VERSION 5.7 ;
  NOWIREEXTENSIONATPIN ON ;
  DIVIDERCHAR "/" ;
  BUSBITCHARS "[]" ;
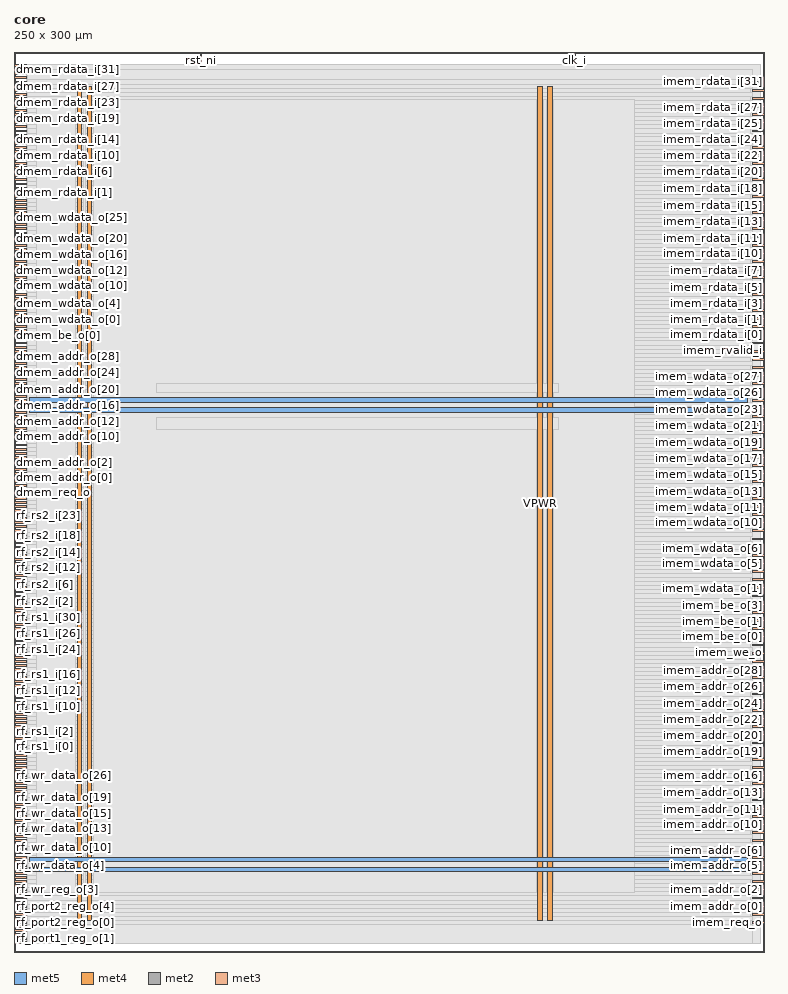
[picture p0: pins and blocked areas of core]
MACRO core
  CLASS BLOCK ;
  FOREIGN core ;
  ORIGIN 0.000 0.000 ;
  SIZE 250.000 BY 300.000 ;
  PIN VGND
    USE GROUND ;
    PORT
      LAYER met5 ;
        RECT 5.280 183.210 244.500 184.810 ;
    END
    PORT
      LAYER met5 ;
        RECT 5.280 30.030 244.500 31.630 ;
    END
    PORT
      LAYER met4 ;
        RECT 177.940 10.640 179.540 288.560 ;
    END
    PORT
      LAYER met4 ;
        RECT 24.340 10.640 25.940 288.560 ;
    END
  END VGND
  PIN VPWR
    USE POWER ;
    PORT
      LAYER met5 ;
        RECT 5.280 179.910 244.500 181.510 ;
    END
    PORT
      LAYER met5 ;
        RECT 5.280 26.730 244.500 28.330 ;
    END
    PORT
      LAYER met4 ;
        RECT 174.640 10.640 176.240 288.560 ;
    END
    PORT
      LAYER met4 ;
        RECT 21.040 10.640 22.640 288.560 ;
    END
  END VPWR
  PIN clk_i
    PORT
      LAYER met2 ;
        RECT 186.850 296.000 187.130 300.000 ;
    END
  END clk_i
  PIN dmem_addr_o[0]
    PORT
      LAYER met3 ;
        RECT 0.000 157.800 4.000 158.400 ;
    END
  END dmem_addr_o[0]
  PIN dmem_addr_o[10]
    PORT
      LAYER met3 ;
        RECT 0.000 171.400 4.000 172.000 ;
    END
  END dmem_addr_o[10]
  PIN dmem_addr_o[11]
    PORT
      LAYER met3 ;
        RECT 0.000 172.760 4.000 173.360 ;
    END
  END dmem_addr_o[11]
  PIN dmem_addr_o[12]
    PORT
      LAYER met3 ;
        RECT 0.000 174.120 4.000 174.720 ;
    END
  END dmem_addr_o[12]
  PIN dmem_addr_o[13]
    PORT
      LAYER met3 ;
        RECT 0.000 175.480 4.000 176.080 ;
    END
  END dmem_addr_o[13]
  PIN dmem_addr_o[14]
    PORT
      LAYER met3 ;
        RECT 0.000 176.840 4.000 177.440 ;
    END
  END dmem_addr_o[14]
  PIN dmem_addr_o[15]
    PORT
      LAYER met3 ;
        RECT 0.000 178.200 4.000 178.800 ;
    END
  END dmem_addr_o[15]
  PIN dmem_addr_o[16]
    PORT
      LAYER met3 ;
        RECT 0.000 179.560 4.000 180.160 ;
    END
  END dmem_addr_o[16]
  PIN dmem_addr_o[17]
    PORT
      LAYER met3 ;
        RECT 0.000 180.920 4.000 181.520 ;
    END
  END dmem_addr_o[17]
  PIN dmem_addr_o[18]
    PORT
      LAYER met3 ;
        RECT 0.000 182.280 4.000 182.880 ;
    END
  END dmem_addr_o[18]
  PIN dmem_addr_o[19]
    PORT
      LAYER met3 ;
        RECT 0.000 183.640 4.000 184.240 ;
    END
  END dmem_addr_o[19]
  PIN dmem_addr_o[1]
    PORT
      LAYER met3 ;
        RECT 0.000 159.160 4.000 159.760 ;
    END
  END dmem_addr_o[1]
  PIN dmem_addr_o[20]
    PORT
      LAYER met3 ;
        RECT 0.000 185.000 4.000 185.600 ;
    END
  END dmem_addr_o[20]
  PIN dmem_addr_o[21]
    PORT
      LAYER met3 ;
        RECT 0.000 186.360 4.000 186.960 ;
    END
  END dmem_addr_o[21]
  PIN dmem_addr_o[22]
    PORT
      LAYER met3 ;
        RECT 0.000 187.720 4.000 188.320 ;
    END
  END dmem_addr_o[22]
  PIN dmem_addr_o[23]
    PORT
      LAYER met3 ;
        RECT 0.000 189.080 4.000 189.680 ;
    END
  END dmem_addr_o[23]
  PIN dmem_addr_o[24]
    PORT
      LAYER met3 ;
        RECT 0.000 190.440 4.000 191.040 ;
    END
  END dmem_addr_o[24]
  PIN dmem_addr_o[25]
    PORT
      LAYER met3 ;
        RECT 0.000 191.800 4.000 192.400 ;
    END
  END dmem_addr_o[25]
  PIN dmem_addr_o[26]
    PORT
      LAYER met3 ;
        RECT 0.000 193.160 4.000 193.760 ;
    END
  END dmem_addr_o[26]
  PIN dmem_addr_o[27]
    PORT
      LAYER met3 ;
        RECT 0.000 194.520 4.000 195.120 ;
    END
  END dmem_addr_o[27]
  PIN dmem_addr_o[28]
    PORT
      LAYER met3 ;
        RECT 0.000 195.880 4.000 196.480 ;
    END
  END dmem_addr_o[28]
  PIN dmem_addr_o[29]
    PORT
      LAYER met3 ;
        RECT 0.000 197.240 4.000 197.840 ;
    END
  END dmem_addr_o[29]
  PIN dmem_addr_o[2]
    PORT
      LAYER met3 ;
        RECT 0.000 160.520 4.000 161.120 ;
    END
  END dmem_addr_o[2]
  PIN dmem_addr_o[30]
    PORT
      LAYER met3 ;
        RECT 0.000 198.600 4.000 199.200 ;
    END
  END dmem_addr_o[30]
  PIN dmem_addr_o[31]
    PORT
      LAYER met3 ;
        RECT 0.000 199.960 4.000 200.560 ;
    END
  END dmem_addr_o[31]
  PIN dmem_addr_o[3]
    PORT
      LAYER met3 ;
        RECT 0.000 161.880 4.000 162.480 ;
    END
  END dmem_addr_o[3]
  PIN dmem_addr_o[4]
    PORT
      LAYER met3 ;
        RECT 0.000 163.240 4.000 163.840 ;
    END
  END dmem_addr_o[4]
  PIN dmem_addr_o[5]
    PORT
      LAYER met3 ;
        RECT 0.000 164.600 4.000 165.200 ;
    END
  END dmem_addr_o[5]
  PIN dmem_addr_o[6]
    PORT
      LAYER met3 ;
        RECT 0.000 165.960 4.000 166.560 ;
    END
  END dmem_addr_o[6]
  PIN dmem_addr_o[7]
    PORT
      LAYER met3 ;
        RECT 0.000 167.320 4.000 167.920 ;
    END
  END dmem_addr_o[7]
  PIN dmem_addr_o[8]
    PORT
      LAYER met3 ;
        RECT 0.000 168.680 4.000 169.280 ;
    END
  END dmem_addr_o[8]
  PIN dmem_addr_o[9]
    PORT
      LAYER met3 ;
        RECT 0.000 170.040 4.000 170.640 ;
    END
  END dmem_addr_o[9]
  PIN dmem_be_o[0]
    PORT
      LAYER met3 ;
        RECT 0.000 202.680 4.000 203.280 ;
    END
  END dmem_be_o[0]
  PIN dmem_be_o[1]
    PORT
      LAYER met3 ;
        RECT 0.000 204.040 4.000 204.640 ;
    END
  END dmem_be_o[1]
  PIN dmem_be_o[2]
    PORT
      LAYER met3 ;
        RECT 0.000 205.400 4.000 206.000 ;
    END
  END dmem_be_o[2]
  PIN dmem_be_o[3]
    PORT
      LAYER met3 ;
        RECT 0.000 206.760 4.000 207.360 ;
    END
  END dmem_be_o[3]
  PIN dmem_gnt_i
    PORT
      LAYER met3 ;
        RECT 0.000 156.440 4.000 157.040 ;
    END
  END dmem_gnt_i
  PIN dmem_rdata_i[0]
    PORT
      LAYER met3 ;
        RECT 0.000 251.640 4.000 252.240 ;
    END
  END dmem_rdata_i[0]
  PIN dmem_rdata_i[10]
    PORT
      LAYER met3 ;
        RECT 0.000 265.240 4.000 265.840 ;
    END
  END dmem_rdata_i[10]
  PIN dmem_rdata_i[11]
    PORT
      LAYER met3 ;
        RECT 0.000 266.600 4.000 267.200 ;
    END
  END dmem_rdata_i[11]
  PIN dmem_rdata_i[12]
    PORT
      LAYER met3 ;
        RECT 0.000 267.960 4.000 268.560 ;
    END
  END dmem_rdata_i[12]
  PIN dmem_rdata_i[13]
    PORT
      LAYER met3 ;
        RECT 0.000 269.320 4.000 269.920 ;
    END
  END dmem_rdata_i[13]
  PIN dmem_rdata_i[14]
    PORT
      LAYER met3 ;
        RECT 0.000 270.680 4.000 271.280 ;
    END
  END dmem_rdata_i[14]
  PIN dmem_rdata_i[15]
    PORT
      LAYER met3 ;
        RECT 0.000 272.040 4.000 272.640 ;
    END
  END dmem_rdata_i[15]
  PIN dmem_rdata_i[16]
    PORT
      LAYER met3 ;
        RECT 0.000 273.400 4.000 274.000 ;
    END
  END dmem_rdata_i[16]
  PIN dmem_rdata_i[17]
    PORT
      LAYER met3 ;
        RECT 0.000 274.760 4.000 275.360 ;
    END
  END dmem_rdata_i[17]
  PIN dmem_rdata_i[18]
    PORT
      LAYER met3 ;
        RECT 0.000 276.120 4.000 276.720 ;
    END
  END dmem_rdata_i[18]
  PIN dmem_rdata_i[19]
    PORT
      LAYER met3 ;
        RECT 0.000 277.480 4.000 278.080 ;
    END
  END dmem_rdata_i[19]
  PIN dmem_rdata_i[1]
    PORT
      LAYER met3 ;
        RECT 0.000 253.000 4.000 253.600 ;
    END
  END dmem_rdata_i[1]
  PIN dmem_rdata_i[20]
    PORT
      LAYER met3 ;
        RECT 0.000 278.840 4.000 279.440 ;
    END
  END dmem_rdata_i[20]
  PIN dmem_rdata_i[21]
    PORT
      LAYER met3 ;
        RECT 0.000 280.200 4.000 280.800 ;
    END
  END dmem_rdata_i[21]
  PIN dmem_rdata_i[22]
    PORT
      LAYER met3 ;
        RECT 0.000 281.560 4.000 282.160 ;
    END
  END dmem_rdata_i[22]
  PIN dmem_rdata_i[23]
    PORT
      LAYER met3 ;
        RECT 0.000 282.920 4.000 283.520 ;
    END
  END dmem_rdata_i[23]
  PIN dmem_rdata_i[24]
    PORT
      LAYER met3 ;
        RECT 0.000 284.280 4.000 284.880 ;
    END
  END dmem_rdata_i[24]
  PIN dmem_rdata_i[25]
    PORT
      LAYER met3 ;
        RECT 0.000 285.640 4.000 286.240 ;
    END
  END dmem_rdata_i[25]
  PIN dmem_rdata_i[26]
    PORT
      LAYER met3 ;
        RECT 0.000 287.000 4.000 287.600 ;
    END
  END dmem_rdata_i[26]
  PIN dmem_rdata_i[27]
    PORT
      LAYER met3 ;
        RECT 0.000 288.360 4.000 288.960 ;
    END
  END dmem_rdata_i[27]
  PIN dmem_rdata_i[28]
    PORT
      LAYER met3 ;
        RECT 0.000 289.720 4.000 290.320 ;
    END
  END dmem_rdata_i[28]
  PIN dmem_rdata_i[29]
    PORT
      LAYER met3 ;
        RECT 0.000 291.080 4.000 291.680 ;
    END
  END dmem_rdata_i[29]
  PIN dmem_rdata_i[2]
    PORT
      LAYER met3 ;
        RECT 0.000 254.360 4.000 254.960 ;
    END
  END dmem_rdata_i[2]
  PIN dmem_rdata_i[30]
    PORT
      LAYER met3 ;
        RECT 0.000 292.440 4.000 293.040 ;
    END
  END dmem_rdata_i[30]
  PIN dmem_rdata_i[31]
    PORT
      LAYER met3 ;
        RECT 0.000 293.800 4.000 294.400 ;
    END
  END dmem_rdata_i[31]
  PIN dmem_rdata_i[3]
    PORT
      LAYER met3 ;
        RECT 0.000 255.720 4.000 256.320 ;
    END
  END dmem_rdata_i[3]
  PIN dmem_rdata_i[4]
    PORT
      LAYER met3 ;
        RECT 0.000 257.080 4.000 257.680 ;
    END
  END dmem_rdata_i[4]
  PIN dmem_rdata_i[5]
    PORT
      LAYER met3 ;
        RECT 0.000 258.440 4.000 259.040 ;
    END
  END dmem_rdata_i[5]
  PIN dmem_rdata_i[6]
    PORT
      LAYER met3 ;
        RECT 0.000 259.800 4.000 260.400 ;
    END
  END dmem_rdata_i[6]
  PIN dmem_rdata_i[7]
    PORT
      LAYER met3 ;
        RECT 0.000 261.160 4.000 261.760 ;
    END
  END dmem_rdata_i[7]
  PIN dmem_rdata_i[8]
    PORT
      LAYER met3 ;
        RECT 0.000 262.520 4.000 263.120 ;
    END
  END dmem_rdata_i[8]
  PIN dmem_rdata_i[9]
    PORT
      LAYER met3 ;
        RECT 0.000 263.880 4.000 264.480 ;
    END
  END dmem_rdata_i[9]
  PIN dmem_req_o
    PORT
      LAYER met3 ;
        RECT 0.000 155.080 4.000 155.680 ;
    END
  END dmem_req_o
  PIN dmem_rvalid_i
    PORT
      LAYER met3 ;
        RECT 0.000 295.160 4.000 295.760 ;
    END
  END dmem_rvalid_i
  PIN dmem_wdata_o[0]
    PORT
      LAYER met3 ;
        RECT 0.000 208.120 4.000 208.720 ;
    END
  END dmem_wdata_o[0]
  PIN dmem_wdata_o[10]
    PORT
      LAYER met3 ;
        RECT 0.000 221.720 4.000 222.320 ;
    END
  END dmem_wdata_o[10]
  PIN dmem_wdata_o[11]
    PORT
      LAYER met3 ;
        RECT 0.000 223.080 4.000 223.680 ;
    END
  END dmem_wdata_o[11]
  PIN dmem_wdata_o[12]
    PORT
      LAYER met3 ;
        RECT 0.000 224.440 4.000 225.040 ;
    END
  END dmem_wdata_o[12]
  PIN dmem_wdata_o[13]
    PORT
      LAYER met3 ;
        RECT 0.000 225.800 4.000 226.400 ;
    END
  END dmem_wdata_o[13]
  PIN dmem_wdata_o[14]
    PORT
      LAYER met3 ;
        RECT 0.000 227.160 4.000 227.760 ;
    END
  END dmem_wdata_o[14]
  PIN dmem_wdata_o[15]
    PORT
      LAYER met3 ;
        RECT 0.000 228.520 4.000 229.120 ;
    END
  END dmem_wdata_o[15]
  PIN dmem_wdata_o[16]
    PORT
      LAYER met3 ;
        RECT 0.000 229.880 4.000 230.480 ;
    END
  END dmem_wdata_o[16]
  PIN dmem_wdata_o[17]
    PORT
      LAYER met3 ;
        RECT 0.000 231.240 4.000 231.840 ;
    END
  END dmem_wdata_o[17]
  PIN dmem_wdata_o[18]
    PORT
      LAYER met3 ;
        RECT 0.000 232.600 4.000 233.200 ;
    END
  END dmem_wdata_o[18]
  PIN dmem_wdata_o[19]
    PORT
      LAYER met3 ;
        RECT 0.000 233.960 4.000 234.560 ;
    END
  END dmem_wdata_o[19]
  PIN dmem_wdata_o[1]
    PORT
      LAYER met3 ;
        RECT 0.000 209.480 4.000 210.080 ;
    END
  END dmem_wdata_o[1]
  PIN dmem_wdata_o[20]
    PORT
      LAYER met3 ;
        RECT 0.000 235.320 4.000 235.920 ;
    END
  END dmem_wdata_o[20]
  PIN dmem_wdata_o[21]
    PORT
      LAYER met3 ;
        RECT 0.000 236.680 4.000 237.280 ;
    END
  END dmem_wdata_o[21]
  PIN dmem_wdata_o[22]
    PORT
      LAYER met3 ;
        RECT 0.000 238.040 4.000 238.640 ;
    END
  END dmem_wdata_o[22]
  PIN dmem_wdata_o[23]
    PORT
      LAYER met3 ;
        RECT 0.000 239.400 4.000 240.000 ;
    END
  END dmem_wdata_o[23]
  PIN dmem_wdata_o[24]
    PORT
      LAYER met3 ;
        RECT 0.000 240.760 4.000 241.360 ;
    END
  END dmem_wdata_o[24]
  PIN dmem_wdata_o[25]
    PORT
      LAYER met3 ;
        RECT 0.000 242.120 4.000 242.720 ;
    END
  END dmem_wdata_o[25]
  PIN dmem_wdata_o[26]
    PORT
      LAYER met3 ;
        RECT 0.000 243.480 4.000 244.080 ;
    END
  END dmem_wdata_o[26]
  PIN dmem_wdata_o[27]
    PORT
      LAYER met3 ;
        RECT 0.000 244.840 4.000 245.440 ;
    END
  END dmem_wdata_o[27]
  PIN dmem_wdata_o[28]
    PORT
      LAYER met3 ;
        RECT 0.000 246.200 4.000 246.800 ;
    END
  END dmem_wdata_o[28]
  PIN dmem_wdata_o[29]
    PORT
      LAYER met3 ;
        RECT 0.000 247.560 4.000 248.160 ;
    END
  END dmem_wdata_o[29]
  PIN dmem_wdata_o[2]
    PORT
      LAYER met3 ;
        RECT 0.000 210.840 4.000 211.440 ;
    END
  END dmem_wdata_o[2]
  PIN dmem_wdata_o[30]
    PORT
      LAYER met3 ;
        RECT 0.000 248.920 4.000 249.520 ;
    END
  END dmem_wdata_o[30]
  PIN dmem_wdata_o[31]
    PORT
      LAYER met3 ;
        RECT 0.000 250.280 4.000 250.880 ;
    END
  END dmem_wdata_o[31]
  PIN dmem_wdata_o[3]
    PORT
      LAYER met3 ;
        RECT 0.000 212.200 4.000 212.800 ;
    END
  END dmem_wdata_o[3]
  PIN dmem_wdata_o[4]
    PORT
      LAYER met3 ;
        RECT 0.000 213.560 4.000 214.160 ;
    END
  END dmem_wdata_o[4]
  PIN dmem_wdata_o[5]
    PORT
      LAYER met3 ;
        RECT 0.000 214.920 4.000 215.520 ;
    END
  END dmem_wdata_o[5]
  PIN dmem_wdata_o[6]
    PORT
      LAYER met3 ;
        RECT 0.000 216.280 4.000 216.880 ;
    END
  END dmem_wdata_o[6]
  PIN dmem_wdata_o[7]
    PORT
      LAYER met3 ;
        RECT 0.000 217.640 4.000 218.240 ;
    END
  END dmem_wdata_o[7]
  PIN dmem_wdata_o[8]
    PORT
      LAYER met3 ;
        RECT 0.000 219.000 4.000 219.600 ;
    END
  END dmem_wdata_o[8]
  PIN dmem_wdata_o[9]
    PORT
      LAYER met3 ;
        RECT 0.000 220.360 4.000 220.960 ;
    END
  END dmem_wdata_o[9]
  PIN dmem_we_o
    PORT
      LAYER met3 ;
        RECT 0.000 201.320 4.000 201.920 ;
    END
  END dmem_we_o
  PIN imem_addr_o[0]
    PORT
      LAYER met3 ;
        RECT 246.000 15.000 250.000 15.600 ;
    END
  END imem_addr_o[0]
  PIN imem_addr_o[10]
    PORT
      LAYER met3 ;
        RECT 246.000 42.200 250.000 42.800 ;
    END
  END imem_addr_o[10]
  PIN imem_addr_o[11]
    PORT
      LAYER met3 ;
        RECT 246.000 44.920 250.000 45.520 ;
    END
  END imem_addr_o[11]
  PIN imem_addr_o[12]
    PORT
      LAYER met3 ;
        RECT 246.000 47.640 250.000 48.240 ;
    END
  END imem_addr_o[12]
  PIN imem_addr_o[13]
    PORT
      LAYER met3 ;
        RECT 246.000 50.360 250.000 50.960 ;
    END
  END imem_addr_o[13]
  PIN imem_addr_o[14]
    PORT
      LAYER met3 ;
        RECT 246.000 53.080 250.000 53.680 ;
    END
  END imem_addr_o[14]
  PIN imem_addr_o[15]
    PORT
      LAYER met3 ;
        RECT 246.000 55.800 250.000 56.400 ;
    END
  END imem_addr_o[15]
  PIN imem_addr_o[16]
    PORT
      LAYER met3 ;
        RECT 246.000 58.520 250.000 59.120 ;
    END
  END imem_addr_o[16]
  PIN imem_addr_o[17]
    PORT
      LAYER met3 ;
        RECT 246.000 61.240 250.000 61.840 ;
    END
  END imem_addr_o[17]
  PIN imem_addr_o[18]
    PORT
      LAYER met3 ;
        RECT 246.000 63.960 250.000 64.560 ;
    END
  END imem_addr_o[18]
  PIN imem_addr_o[19]
    PORT
      LAYER met3 ;
        RECT 246.000 66.680 250.000 67.280 ;
    END
  END imem_addr_o[19]
  PIN imem_addr_o[1]
    PORT
      LAYER met3 ;
        RECT 246.000 17.720 250.000 18.320 ;
    END
  END imem_addr_o[1]
  PIN imem_addr_o[20]
    PORT
      LAYER met3 ;
        RECT 246.000 69.400 250.000 70.000 ;
    END
  END imem_addr_o[20]
  PIN imem_addr_o[21]
    PORT
      LAYER met3 ;
        RECT 246.000 72.120 250.000 72.720 ;
    END
  END imem_addr_o[21]
  PIN imem_addr_o[22]
    PORT
      LAYER met3 ;
        RECT 246.000 74.840 250.000 75.440 ;
    END
  END imem_addr_o[22]
  PIN imem_addr_o[23]
    PORT
      LAYER met3 ;
        RECT 246.000 77.560 250.000 78.160 ;
    END
  END imem_addr_o[23]
  PIN imem_addr_o[24]
    PORT
      LAYER met3 ;
        RECT 246.000 80.280 250.000 80.880 ;
    END
  END imem_addr_o[24]
  PIN imem_addr_o[25]
    PORT
      LAYER met3 ;
        RECT 246.000 83.000 250.000 83.600 ;
    END
  END imem_addr_o[25]
  PIN imem_addr_o[26]
    PORT
      LAYER met3 ;
        RECT 246.000 85.720 250.000 86.320 ;
    END
  END imem_addr_o[26]
  PIN imem_addr_o[27]
    PORT
      LAYER met3 ;
        RECT 246.000 88.440 250.000 89.040 ;
    END
  END imem_addr_o[27]
  PIN imem_addr_o[28]
    PORT
      LAYER met3 ;
        RECT 246.000 91.160 250.000 91.760 ;
    END
  END imem_addr_o[28]
  PIN imem_addr_o[29]
    PORT
      LAYER met3 ;
        RECT 246.000 93.880 250.000 94.480 ;
    END
  END imem_addr_o[29]
  PIN imem_addr_o[2]
    PORT
      LAYER met3 ;
        RECT 246.000 20.440 250.000 21.040 ;
    END
  END imem_addr_o[2]
  PIN imem_addr_o[30]
    PORT
      LAYER met3 ;
        RECT 246.000 96.600 250.000 97.200 ;
    END
  END imem_addr_o[30]
  PIN imem_addr_o[31]
    PORT
      LAYER met3 ;
        RECT 246.000 99.320 250.000 99.920 ;
    END
  END imem_addr_o[31]
  PIN imem_addr_o[3]
    PORT
      LAYER met3 ;
        RECT 246.000 23.160 250.000 23.760 ;
    END
  END imem_addr_o[3]
  PIN imem_addr_o[4]
    PORT
      LAYER met3 ;
        RECT 246.000 25.880 250.000 26.480 ;
    END
  END imem_addr_o[4]
  PIN imem_addr_o[5]
    PORT
      LAYER met3 ;
        RECT 246.000 28.600 250.000 29.200 ;
    END
  END imem_addr_o[5]
  PIN imem_addr_o[6]
    PORT
      LAYER met3 ;
        RECT 246.000 31.320 250.000 31.920 ;
    END
  END imem_addr_o[6]
  PIN imem_addr_o[7]
    PORT
      LAYER met3 ;
        RECT 246.000 34.040 250.000 34.640 ;
    END
  END imem_addr_o[7]
  PIN imem_addr_o[8]
    PORT
      LAYER met3 ;
        RECT 246.000 36.760 250.000 37.360 ;
    END
  END imem_addr_o[8]
  PIN imem_addr_o[9]
    PORT
      LAYER met3 ;
        RECT 246.000 39.480 250.000 40.080 ;
    END
  END imem_addr_o[9]
  PIN imem_be_o[0]
    PORT
      LAYER met3 ;
        RECT 246.000 104.760 250.000 105.360 ;
    END
  END imem_be_o[0]
  PIN imem_be_o[1]
    PORT
      LAYER met3 ;
        RECT 246.000 107.480 250.000 108.080 ;
    END
  END imem_be_o[1]
  PIN imem_be_o[2]
    PORT
      LAYER met3 ;
        RECT 246.000 110.200 250.000 110.800 ;
    END
  END imem_be_o[2]
  PIN imem_be_o[3]
    PORT
      LAYER met3 ;
        RECT 246.000 112.920 250.000 113.520 ;
    END
  END imem_be_o[3]
  PIN imem_gnt_i
    PORT
      LAYER met3 ;
        RECT 246.000 12.280 250.000 12.880 ;
    END
  END imem_gnt_i
  PIN imem_rdata_i[0]
    PORT
      LAYER met3 ;
        RECT 246.000 205.400 250.000 206.000 ;
    END
  END imem_rdata_i[0]
  PIN imem_rdata_i[10]
    PORT
      LAYER met3 ;
        RECT 246.000 232.600 250.000 233.200 ;
    END
  END imem_rdata_i[10]
  PIN imem_rdata_i[11]
    PORT
      LAYER met3 ;
        RECT 246.000 235.320 250.000 235.920 ;
    END
  END imem_rdata_i[11]
  PIN imem_rdata_i[12]
    PORT
      LAYER met3 ;
        RECT 246.000 238.040 250.000 238.640 ;
    END
  END imem_rdata_i[12]
  PIN imem_rdata_i[13]
    PORT
      LAYER met3 ;
        RECT 246.000 240.760 250.000 241.360 ;
    END
  END imem_rdata_i[13]
  PIN imem_rdata_i[14]
    PORT
      LAYER met3 ;
        RECT 246.000 243.480 250.000 244.080 ;
    END
  END imem_rdata_i[14]
  PIN imem_rdata_i[15]
    PORT
      LAYER met3 ;
        RECT 246.000 246.200 250.000 246.800 ;
    END
  END imem_rdata_i[15]
  PIN imem_rdata_i[16]
    PORT
      LAYER met3 ;
        RECT 246.000 248.920 250.000 249.520 ;
    END
  END imem_rdata_i[16]
  PIN imem_rdata_i[17]
    PORT
      LAYER met3 ;
        RECT 246.000 251.640 250.000 252.240 ;
    END
  END imem_rdata_i[17]
  PIN imem_rdata_i[18]
    PORT
      LAYER met3 ;
        RECT 246.000 254.360 250.000 254.960 ;
    END
  END imem_rdata_i[18]
  PIN imem_rdata_i[19]
    PORT
      LAYER met3 ;
        RECT 246.000 257.080 250.000 257.680 ;
    END
  END imem_rdata_i[19]
  PIN imem_rdata_i[1]
    PORT
      LAYER met3 ;
        RECT 246.000 208.120 250.000 208.720 ;
    END
  END imem_rdata_i[1]
  PIN imem_rdata_i[20]
    PORT
      LAYER met3 ;
        RECT 246.000 259.800 250.000 260.400 ;
    END
  END imem_rdata_i[20]
  PIN imem_rdata_i[21]
    PORT
      LAYER met3 ;
        RECT 246.000 262.520 250.000 263.120 ;
    END
  END imem_rdata_i[21]
  PIN imem_rdata_i[22]
    PORT
      LAYER met3 ;
        RECT 246.000 265.240 250.000 265.840 ;
    END
  END imem_rdata_i[22]
  PIN imem_rdata_i[23]
    PORT
      LAYER met3 ;
        RECT 246.000 267.960 250.000 268.560 ;
    END
  END imem_rdata_i[23]
  PIN imem_rdata_i[24]
    PORT
      LAYER met3 ;
        RECT 246.000 270.680 250.000 271.280 ;
    END
  END imem_rdata_i[24]
  PIN imem_rdata_i[25]
    PORT
      LAYER met3 ;
        RECT 246.000 273.400 250.000 274.000 ;
    END
  END imem_rdata_i[25]
  PIN imem_rdata_i[26]
    PORT
      LAYER met3 ;
        RECT 246.000 276.120 250.000 276.720 ;
    END
  END imem_rdata_i[26]
  PIN imem_rdata_i[27]
    PORT
      LAYER met3 ;
        RECT 246.000 278.840 250.000 279.440 ;
    END
  END imem_rdata_i[27]
  PIN imem_rdata_i[28]
    PORT
      LAYER met3 ;
        RECT 246.000 281.560 250.000 282.160 ;
    END
  END imem_rdata_i[28]
  PIN imem_rdata_i[29]
    PORT
      LAYER met3 ;
        RECT 246.000 284.280 250.000 284.880 ;
    END
  END imem_rdata_i[29]
  PIN imem_rdata_i[2]
    PORT
      LAYER met3 ;
        RECT 246.000 210.840 250.000 211.440 ;
    END
  END imem_rdata_i[2]
  PIN imem_rdata_i[30]
    PORT
      LAYER met3 ;
        RECT 246.000 287.000 250.000 287.600 ;
    END
  END imem_rdata_i[30]
  PIN imem_rdata_i[31]
    PORT
      LAYER met3 ;
        RECT 246.000 289.720 250.000 290.320 ;
    END
  END imem_rdata_i[31]
  PIN imem_rdata_i[3]
    PORT
      LAYER met3 ;
        RECT 246.000 213.560 250.000 214.160 ;
    END
  END imem_rdata_i[3]
  PIN imem_rdata_i[4]
    PORT
      LAYER met3 ;
        RECT 246.000 216.280 250.000 216.880 ;
    END
  END imem_rdata_i[4]
  PIN imem_rdata_i[5]
    PORT
      LAYER met3 ;
        RECT 246.000 219.000 250.000 219.600 ;
    END
  END imem_rdata_i[5]
  PIN imem_rdata_i[6]
    PORT
      LAYER met3 ;
        RECT 246.000 221.720 250.000 222.320 ;
    END
  END imem_rdata_i[6]
  PIN imem_rdata_i[7]
    PORT
      LAYER met3 ;
        RECT 246.000 224.440 250.000 225.040 ;
    END
  END imem_rdata_i[7]
  PIN imem_rdata_i[8]
    PORT
      LAYER met3 ;
        RECT 246.000 227.160 250.000 227.760 ;
    END
  END imem_rdata_i[8]
  PIN imem_rdata_i[9]
    PORT
      LAYER met3 ;
        RECT 246.000 229.880 250.000 230.480 ;
    END
  END imem_rdata_i[9]
  PIN imem_req_o
    PORT
      LAYER met3 ;
        RECT 246.000 9.560 250.000 10.160 ;
    END
  END imem_req_o
  PIN imem_rvalid_i
    PORT
      LAYER met3 ;
        RECT 246.000 202.680 250.000 203.280 ;
    END
  END imem_rvalid_i
  PIN imem_wdata_o[0]
    PORT
      LAYER met3 ;
        RECT 246.000 115.640 250.000 116.240 ;
    END
  END imem_wdata_o[0]
  PIN imem_wdata_o[10]
    PORT
      LAYER met3 ;
        RECT 246.000 142.840 250.000 143.440 ;
    END
  END imem_wdata_o[10]
  PIN imem_wdata_o[11]
    PORT
      LAYER met3 ;
        RECT 246.000 145.560 250.000 146.160 ;
    END
  END imem_wdata_o[11]
  PIN imem_wdata_o[12]
    PORT
      LAYER met3 ;
        RECT 246.000 148.280 250.000 148.880 ;
    END
  END imem_wdata_o[12]
  PIN imem_wdata_o[13]
    PORT
      LAYER met3 ;
        RECT 246.000 151.000 250.000 151.600 ;
    END
  END imem_wdata_o[13]
  PIN imem_wdata_o[14]
    PORT
      LAYER met3 ;
        RECT 246.000 153.720 250.000 154.320 ;
    END
  END imem_wdata_o[14]
  PIN imem_wdata_o[15]
    PORT
      LAYER met3 ;
        RECT 246.000 156.440 250.000 157.040 ;
    END
  END imem_wdata_o[15]
  PIN imem_wdata_o[16]
    PORT
      LAYER met3 ;
        RECT 246.000 159.160 250.000 159.760 ;
    END
  END imem_wdata_o[16]
  PIN imem_wdata_o[17]
    PORT
      LAYER met3 ;
        RECT 246.000 161.880 250.000 162.480 ;
    END
  END imem_wdata_o[17]
  PIN imem_wdata_o[18]
    PORT
      LAYER met3 ;
        RECT 246.000 164.600 250.000 165.200 ;
    END
  END imem_wdata_o[18]
  PIN imem_wdata_o[19]
    PORT
      LAYER met3 ;
        RECT 246.000 167.320 250.000 167.920 ;
    END
  END imem_wdata_o[19]
  PIN imem_wdata_o[1]
    PORT
      LAYER met3 ;
        RECT 246.000 118.360 250.000 118.960 ;
    END
  END imem_wdata_o[1]
  PIN imem_wdata_o[20]
    PORT
      LAYER met3 ;
        RECT 246.000 170.040 250.000 170.640 ;
    END
  END imem_wdata_o[20]
  PIN imem_wdata_o[21]
    PORT
      LAYER met3 ;
        RECT 246.000 172.760 250.000 173.360 ;
    END
  END imem_wdata_o[21]
  PIN imem_wdata_o[22]
    PORT
      LAYER met3 ;
        RECT 246.000 175.480 250.000 176.080 ;
    END
  END imem_wdata_o[22]
  PIN imem_wdata_o[23]
    PORT
      LAYER met3 ;
        RECT 246.000 178.200 250.000 178.800 ;
    END
  END imem_wdata_o[23]
  PIN imem_wdata_o[24]
    PORT
      LAYER met3 ;
        RECT 246.000 180.920 250.000 181.520 ;
    END
  END imem_wdata_o[24]
  PIN imem_wdata_o[25]
    PORT
      LAYER met3 ;
        RECT 246.000 183.640 250.000 184.240 ;
    END
  END imem_wdata_o[25]
  PIN imem_wdata_o[26]
    PORT
      LAYER met3 ;
        RECT 246.000 186.360 250.000 186.960 ;
    END
  END imem_wdata_o[26]
  PIN imem_wdata_o[27]
    PORT
      LAYER met3 ;
        RECT 246.000 189.080 250.000 189.680 ;
    END
  END imem_wdata_o[27]
  PIN imem_wdata_o[28]
    PORT
      LAYER met3 ;
        RECT 246.000 191.800 250.000 192.400 ;
    END
  END imem_wdata_o[28]
  PIN imem_wdata_o[29]
    PORT
      LAYER met3 ;
        RECT 246.000 194.520 250.000 195.120 ;
    END
  END imem_wdata_o[29]
  PIN imem_wdata_o[2]
    PORT
      LAYER met3 ;
        RECT 246.000 121.080 250.000 121.680 ;
    END
  END imem_wdata_o[2]
  PIN imem_wdata_o[30]
    PORT
      LAYER met3 ;
        RECT 246.000 197.240 250.000 197.840 ;
    END
  END imem_wdata_o[30]
  PIN imem_wdata_o[31]
    PORT
      LAYER met3 ;
        RECT 246.000 199.960 250.000 200.560 ;
    END
  END imem_wdata_o[31]
  PIN imem_wdata_o[3]
    PORT
      LAYER met3 ;
        RECT 246.000 123.800 250.000 124.400 ;
    END
  END imem_wdata_o[3]
  PIN imem_wdata_o[4]
    PORT
      LAYER met3 ;
        RECT 246.000 126.520 250.000 127.120 ;
    END
  END imem_wdata_o[4]
  PIN imem_wdata_o[5]
    PORT
      LAYER met3 ;
        RECT 246.000 129.240 250.000 129.840 ;
    END
  END imem_wdata_o[5]
  PIN imem_wdata_o[6]
    PORT
      LAYER met3 ;
        RECT 246.000 131.960 250.000 132.560 ;
    END
  END imem_wdata_o[6]
  PIN imem_wdata_o[7]
    PORT
      LAYER met3 ;
        RECT 246.000 134.680 250.000 135.280 ;
    END
  END imem_wdata_o[7]
  PIN imem_wdata_o[8]
    PORT
      LAYER met3 ;
        RECT 246.000 137.400 250.000 138.000 ;
    END
  END imem_wdata_o[8]
  PIN imem_wdata_o[9]
    PORT
      LAYER met3 ;
        RECT 246.000 140.120 250.000 140.720 ;
    END
  END imem_wdata_o[9]
  PIN imem_we_o
    PORT
      LAYER met3 ;
        RECT 246.000 102.040 250.000 102.640 ;
    END
  END imem_we_o
  PIN rf_port1_reg_o[0]
    PORT
      LAYER met3 ;
        RECT 0.000 2.760 4.000 3.360 ;
    END
  END rf_port1_reg_o[0]
  PIN rf_port1_reg_o[1]
    PORT
      LAYER met3 ;
        RECT 0.000 4.120 4.000 4.720 ;
    END
  END rf_port1_reg_o[1]
  PIN rf_port1_reg_o[2]
    PORT
      LAYER met3 ;
        RECT 0.000 5.480 4.000 6.080 ;
    END
  END rf_port1_reg_o[2]
  PIN rf_port1_reg_o[3]
    PORT
      LAYER met3 ;
        RECT 0.000 6.840 4.000 7.440 ;
    END
  END rf_port1_reg_o[3]
  PIN rf_port1_reg_o[4]
    PORT
      LAYER met3 ;
        RECT 0.000 8.200 4.000 8.800 ;
    END
  END rf_port1_reg_o[4]
  PIN rf_port2_reg_o[0]
    PORT
      LAYER met3 ;
        RECT 0.000 9.560 4.000 10.160 ;
    END
  END rf_port2_reg_o[0]
  PIN rf_port2_reg_o[1]
    PORT
      LAYER met3 ;
        RECT 0.000 10.920 4.000 11.520 ;
    END
  END rf_port2_reg_o[1]
  PIN rf_port2_reg_o[2]
    PORT
      LAYER met3 ;
        RECT 0.000 12.280 4.000 12.880 ;
    END
  END rf_port2_reg_o[2]
  PIN rf_port2_reg_o[3]
    PORT
      LAYER met3 ;
        RECT 0.000 13.640 4.000 14.240 ;
    END
  END rf_port2_reg_o[3]
  PIN rf_port2_reg_o[4]
    PORT
      LAYER met3 ;
        RECT 0.000 15.000 4.000 15.600 ;
    END
  END rf_port2_reg_o[4]
  PIN rf_rs1_i[0]
    PORT
      LAYER met3 ;
        RECT 0.000 68.040 4.000 68.640 ;
    END
  END rf_rs1_i[0]
  PIN rf_rs1_i[10]
    PORT
      LAYER met3 ;
        RECT 0.000 81.640 4.000 82.240 ;
    END
  END rf_rs1_i[10]
  PIN rf_rs1_i[11]
    PORT
      LAYER met3 ;
        RECT 0.000 83.000 4.000 83.600 ;
    END
  END rf_rs1_i[11]
  PIN rf_rs1_i[12]
    PORT
      LAYER met3 ;
        RECT 0.000 84.360 4.000 84.960 ;
    END
  END rf_rs1_i[12]
  PIN rf_rs1_i[13]
    PORT
      LAYER met3 ;
        RECT 0.000 85.720 4.000 86.320 ;
    END
  END rf_rs1_i[13]
  PIN rf_rs1_i[14]
    PORT
      LAYER met3 ;
        RECT 0.000 87.080 4.000 87.680 ;
    END
  END rf_rs1_i[14]
  PIN rf_rs1_i[15]
    PORT
      LAYER met3 ;
        RECT 0.000 88.440 4.000 89.040 ;
    END
  END rf_rs1_i[15]
  PIN rf_rs1_i[16]
    PORT
      LAYER met3 ;
        RECT 0.000 89.800 4.000 90.400 ;
    END
  END rf_rs1_i[16]
  PIN rf_rs1_i[17]
    PORT
      LAYER met3 ;
        RECT 0.000 91.160 4.000 91.760 ;
    END
  END rf_rs1_i[17]
  PIN rf_rs1_i[18]
    PORT
      LAYER met3 ;
        RECT 0.000 92.520 4.000 93.120 ;
    END
  END rf_rs1_i[18]
  PIN rf_rs1_i[19]
    PORT
      LAYER met3 ;
        RECT 0.000 93.880 4.000 94.480 ;
    END
  END rf_rs1_i[19]
  PIN rf_rs1_i[1]
    PORT
      LAYER met3 ;
        RECT 0.000 69.400 4.000 70.000 ;
    END
  END rf_rs1_i[1]
  PIN rf_rs1_i[20]
    PORT
      LAYER met3 ;
        RECT 0.000 95.240 4.000 95.840 ;
    END
  END rf_rs1_i[20]
  PIN rf_rs1_i[21]
    PORT
      LAYER met3 ;
        RECT 0.000 96.600 4.000 97.200 ;
    END
  END rf_rs1_i[21]
  PIN rf_rs1_i[22]
    PORT
      LAYER met3 ;
        RECT 0.000 97.960 4.000 98.560 ;
    END
  END rf_rs1_i[22]
  PIN rf_rs1_i[23]
    PORT
      LAYER met3 ;
        RECT 0.000 99.320 4.000 99.920 ;
    END
  END rf_rs1_i[23]
  PIN rf_rs1_i[24]
    PORT
      LAYER met3 ;
        RECT 0.000 100.680 4.000 101.280 ;
    END
  END rf_rs1_i[24]
  PIN rf_rs1_i[25]
    PORT
      LAYER met3 ;
        RECT 0.000 102.040 4.000 102.640 ;
    END
  END rf_rs1_i[25]
  PIN rf_rs1_i[26]
    PORT
      LAYER met3 ;
        RECT 0.000 103.400 4.000 104.000 ;
    END
  END rf_rs1_i[26]
  PIN rf_rs1_i[27]
    PORT
      LAYER met3 ;
        RECT 0.000 104.760 4.000 105.360 ;
    END
  END rf_rs1_i[27]
  PIN rf_rs1_i[28]
    PORT
      LAYER met3 ;
        RECT 0.000 106.120 4.000 106.720 ;
    END
  END rf_rs1_i[28]
  PIN rf_rs1_i[29]
    PORT
      LAYER met3 ;
        RECT 0.000 107.480 4.000 108.080 ;
    END
  END rf_rs1_i[29]
  PIN rf_rs1_i[2]
    PORT
      LAYER met3 ;
        RECT 0.000 70.760 4.000 71.360 ;
    END
  END rf_rs1_i[2]
  PIN rf_rs1_i[30]
    PORT
      LAYER met3 ;
        RECT 0.000 108.840 4.000 109.440 ;
    END
  END rf_rs1_i[30]
  PIN rf_rs1_i[31]
    PORT
      LAYER met3 ;
        RECT 0.000 110.200 4.000 110.800 ;
    END
  END rf_rs1_i[31]
  PIN rf_rs1_i[3]
    PORT
      LAYER met3 ;
        RECT 0.000 72.120 4.000 72.720 ;
    END
  END rf_rs1_i[3]
  PIN rf_rs1_i[4]
    PORT
      LAYER met3 ;
        RECT 0.000 73.480 4.000 74.080 ;
    END
  END rf_rs1_i[4]
  PIN rf_rs1_i[5]
    PORT
      LAYER met3 ;
        RECT 0.000 74.840 4.000 75.440 ;
    END
  END rf_rs1_i[5]
  PIN rf_rs1_i[6]
    PORT
      LAYER met3 ;
        RECT 0.000 76.200 4.000 76.800 ;
    END
  END rf_rs1_i[6]
  PIN rf_rs1_i[7]
    PORT
      LAYER met3 ;
        RECT 0.000 77.560 4.000 78.160 ;
    END
  END rf_rs1_i[7]
  PIN rf_rs1_i[8]
    PORT
      LAYER met3 ;
        RECT 0.000 78.920 4.000 79.520 ;
    END
  END rf_rs1_i[8]
  PIN rf_rs1_i[9]
    PORT
      LAYER met3 ;
        RECT 0.000 80.280 4.000 80.880 ;
    END
  END rf_rs1_i[9]
  PIN rf_rs2_i[0]
    PORT
      LAYER met3 ;
        RECT 0.000 111.560 4.000 112.160 ;
    END
  END rf_rs2_i[0]
  PIN rf_rs2_i[10]
    PORT
      LAYER met3 ;
        RECT 0.000 125.160 4.000 125.760 ;
    END
  END rf_rs2_i[10]
  PIN rf_rs2_i[11]
    PORT
      LAYER met3 ;
        RECT 0.000 126.520 4.000 127.120 ;
    END
  END rf_rs2_i[11]
  PIN rf_rs2_i[12]
    PORT
      LAYER met3 ;
        RECT 0.000 127.880 4.000 128.480 ;
    END
  END rf_rs2_i[12]
  PIN rf_rs2_i[13]
    PORT
      LAYER met3 ;
        RECT 0.000 129.240 4.000 129.840 ;
    END
  END rf_rs2_i[13]
  PIN rf_rs2_i[14]
    PORT
      LAYER met3 ;
        RECT 0.000 130.600 4.000 131.200 ;
    END
  END rf_rs2_i[14]
  PIN rf_rs2_i[15]
    PORT
      LAYER met3 ;
        RECT 0.000 131.960 4.000 132.560 ;
    END
  END rf_rs2_i[15]
  PIN rf_rs2_i[16]
    PORT
      LAYER met3 ;
        RECT 0.000 133.320 4.000 133.920 ;
    END
  END rf_rs2_i[16]
  PIN rf_rs2_i[17]
    PORT
      LAYER met3 ;
        RECT 0.000 134.680 4.000 135.280 ;
    END
  END rf_rs2_i[17]
  PIN rf_rs2_i[18]
    PORT
      LAYER met3 ;
        RECT 0.000 136.040 4.000 136.640 ;
    END
  END rf_rs2_i[18]
  PIN rf_rs2_i[19]
    PORT
      LAYER met3 ;
        RECT 0.000 137.400 4.000 138.000 ;
    END
  END rf_rs2_i[19]
  PIN rf_rs2_i[1]
    PORT
      LAYER met3 ;
        RECT 0.000 112.920 4.000 113.520 ;
    END
  END rf_rs2_i[1]
  PIN rf_rs2_i[20]
    PORT
      LAYER met3 ;
        RECT 0.000 138.760 4.000 139.360 ;
    END
  END rf_rs2_i[20]
  PIN rf_rs2_i[21]
    PORT
      LAYER met3 ;
        RECT 0.000 140.120 4.000 140.720 ;
    END
  END rf_rs2_i[21]
  PIN rf_rs2_i[22]
    PORT
      LAYER met3 ;
        RECT 0.000 141.480 4.000 142.080 ;
    END
  END rf_rs2_i[22]
  PIN rf_rs2_i[23]
    PORT
      LAYER met3 ;
        RECT 0.000 142.840 4.000 143.440 ;
    END
  END rf_rs2_i[23]
  PIN rf_rs2_i[24]
    PORT
      LAYER met3 ;
        RECT 0.000 144.200 4.000 144.800 ;
    END
  END rf_rs2_i[24]
  PIN rf_rs2_i[25]
    PORT
      LAYER met3 ;
        RECT 0.000 145.560 4.000 146.160 ;
    END
  END rf_rs2_i[25]
  PIN rf_rs2_i[26]
    PORT
      LAYER met3 ;
        RECT 0.000 146.920 4.000 147.520 ;
    END
  END rf_rs2_i[26]
  PIN rf_rs2_i[27]
    PORT
      LAYER met3 ;
        RECT 0.000 148.280 4.000 148.880 ;
    END
  END rf_rs2_i[27]
  PIN rf_rs2_i[28]
    PORT
      LAYER met3 ;
        RECT 0.000 149.640 4.000 150.240 ;
    END
  END rf_rs2_i[28]
  PIN rf_rs2_i[29]
    PORT
      LAYER met3 ;
        RECT 0.000 151.000 4.000 151.600 ;
    END
  END rf_rs2_i[29]
  PIN rf_rs2_i[2]
    PORT
      LAYER met3 ;
        RECT 0.000 114.280 4.000 114.880 ;
    END
  END rf_rs2_i[2]
  PIN rf_rs2_i[30]
    PORT
      LAYER met3 ;
        RECT 0.000 152.360 4.000 152.960 ;
    END
  END rf_rs2_i[30]
  PIN rf_rs2_i[31]
    PORT
      LAYER met3 ;
        RECT 0.000 153.720 4.000 154.320 ;
    END
  END rf_rs2_i[31]
  PIN rf_rs2_i[3]
    PORT
      LAYER met3 ;
        RECT 0.000 115.640 4.000 116.240 ;
    END
  END rf_rs2_i[3]
  PIN rf_rs2_i[4]
    PORT
      LAYER met3 ;
        RECT 0.000 117.000 4.000 117.600 ;
    END
  END rf_rs2_i[4]
  PIN rf_rs2_i[5]
    PORT
      LAYER met3 ;
        RECT 0.000 118.360 4.000 118.960 ;
    END
  END rf_rs2_i[5]
  PIN rf_rs2_i[6]
    PORT
      LAYER met3 ;
        RECT 0.000 119.720 4.000 120.320 ;
    END
  END rf_rs2_i[6]
  PIN rf_rs2_i[7]
    PORT
      LAYER met3 ;
        RECT 0.000 121.080 4.000 121.680 ;
    END
  END rf_rs2_i[7]
  PIN rf_rs2_i[8]
    PORT
      LAYER met3 ;
        RECT 0.000 122.440 4.000 123.040 ;
    END
  END rf_rs2_i[8]
  PIN rf_rs2_i[9]
    PORT
      LAYER met3 ;
        RECT 0.000 123.800 4.000 124.400 ;
    END
  END rf_rs2_i[9]
  PIN rf_wr_data_o[0]
    PORT
      LAYER met3 ;
        RECT 0.000 23.160 4.000 23.760 ;
    END
  END rf_wr_data_o[0]
  PIN rf_wr_data_o[10]
    PORT
      LAYER met3 ;
        RECT 0.000 36.760 4.000 37.360 ;
    END
  END rf_wr_data_o[10]
  PIN rf_wr_data_o[11]
    PORT
      LAYER met3 ;
        RECT 0.000 38.120 4.000 38.720 ;
    END
  END rf_wr_data_o[11]
  PIN rf_wr_data_o[12]
    PORT
      LAYER met3 ;
        RECT 0.000 39.480 4.000 40.080 ;
    END
  END rf_wr_data_o[12]
  PIN rf_wr_data_o[13]
    PORT
      LAYER met3 ;
        RECT 0.000 40.840 4.000 41.440 ;
    END
  END rf_wr_data_o[13]
  PIN rf_wr_data_o[14]
    PORT
      LAYER met3 ;
        RECT 0.000 42.200 4.000 42.800 ;
    END
  END rf_wr_data_o[14]
  PIN rf_wr_data_o[15]
    PORT
      LAYER met3 ;
        RECT 0.000 43.560 4.000 44.160 ;
    END
  END rf_wr_data_o[15]
  PIN rf_wr_data_o[16]
    PORT
      LAYER met3 ;
        RECT 0.000 44.920 4.000 45.520 ;
    END
  END rf_wr_data_o[16]
  PIN rf_wr_data_o[17]
    PORT
      LAYER met3 ;
        RECT 0.000 46.280 4.000 46.880 ;
    END
  END rf_wr_data_o[17]
  PIN rf_wr_data_o[18]
    PORT
      LAYER met3 ;
        RECT 0.000 47.640 4.000 48.240 ;
    END
  END rf_wr_data_o[18]
  PIN rf_wr_data_o[19]
    PORT
      LAYER met3 ;
        RECT 0.000 49.000 4.000 49.600 ;
    END
  END rf_wr_data_o[19]
  PIN rf_wr_data_o[1]
    PORT
      LAYER met3 ;
        RECT 0.000 24.520 4.000 25.120 ;
    END
  END rf_wr_data_o[1]
  PIN rf_wr_data_o[20]
    PORT
      LAYER met3 ;
        RECT 0.000 50.360 4.000 50.960 ;
    END
  END rf_wr_data_o[20]
  PIN rf_wr_data_o[21]
    PORT
      LAYER met3 ;
        RECT 0.000 51.720 4.000 52.320 ;
    END
  END rf_wr_data_o[21]
  PIN rf_wr_data_o[22]
    PORT
      LAYER met3 ;
        RECT 0.000 53.080 4.000 53.680 ;
    END
  END rf_wr_data_o[22]
  PIN rf_wr_data_o[23]
    PORT
      LAYER met3 ;
        RECT 0.000 54.440 4.000 55.040 ;
    END
  END rf_wr_data_o[23]
  PIN rf_wr_data_o[24]
    PORT
      LAYER met3 ;
        RECT 0.000 55.800 4.000 56.400 ;
    END
  END rf_wr_data_o[24]
  PIN rf_wr_data_o[25]
    PORT
      LAYER met3 ;
        RECT 0.000 57.160 4.000 57.760 ;
    END
  END rf_wr_data_o[25]
  PIN rf_wr_data_o[26]
    PORT
      LAYER met3 ;
        RECT 0.000 58.520 4.000 59.120 ;
    END
  END rf_wr_data_o[26]
  PIN rf_wr_data_o[27]
    PORT
      LAYER met3 ;
        RECT 0.000 59.880 4.000 60.480 ;
    END
  END rf_wr_data_o[27]
  PIN rf_wr_data_o[28]
    PORT
      LAYER met3 ;
        RECT 0.000 61.240 4.000 61.840 ;
    END
  END rf_wr_data_o[28]
  PIN rf_wr_data_o[29]
    PORT
      LAYER met3 ;
        RECT 0.000 62.600 4.000 63.200 ;
    END
  END rf_wr_data_o[29]
  PIN rf_wr_data_o[2]
    PORT
      LAYER met3 ;
        RECT 0.000 25.880 4.000 26.480 ;
    END
  END rf_wr_data_o[2]
  PIN rf_wr_data_o[30]
    PORT
      LAYER met3 ;
        RECT 0.000 63.960 4.000 64.560 ;
    END
  END rf_wr_data_o[30]
  PIN rf_wr_data_o[31]
    PORT
      LAYER met3 ;
        RECT 0.000 65.320 4.000 65.920 ;
    END
  END rf_wr_data_o[31]
  PIN rf_wr_data_o[3]
    PORT
      LAYER met3 ;
        RECT 0.000 27.240 4.000 27.840 ;
    END
  END rf_wr_data_o[3]
  PIN rf_wr_data_o[4]
    PORT
      LAYER met3 ;
        RECT 0.000 28.600 4.000 29.200 ;
    END
  END rf_wr_data_o[4]
  PIN rf_wr_data_o[5]
    PORT
      LAYER met3 ;
        RECT 0.000 29.960 4.000 30.560 ;
    END
  END rf_wr_data_o[5]
  PIN rf_wr_data_o[6]
    PORT
      LAYER met3 ;
        RECT 0.000 31.320 4.000 31.920 ;
    END
  END rf_wr_data_o[6]
  PIN rf_wr_data_o[7]
    PORT
      LAYER met3 ;
        RECT 0.000 32.680 4.000 33.280 ;
    END
  END rf_wr_data_o[7]
  PIN rf_wr_data_o[8]
    PORT
      LAYER met3 ;
        RECT 0.000 34.040 4.000 34.640 ;
    END
  END rf_wr_data_o[8]
  PIN rf_wr_data_o[9]
    PORT
      LAYER met3 ;
        RECT 0.000 35.400 4.000 36.000 ;
    END
  END rf_wr_data_o[9]
  PIN rf_wr_en_o
    PORT
      LAYER met3 ;
        RECT 0.000 66.680 4.000 67.280 ;
    END
  END rf_wr_en_o
  PIN rf_wr_reg_o[0]
    PORT
      LAYER met3 ;
        RECT 0.000 16.360 4.000 16.960 ;
    END
  END rf_wr_reg_o[0]
  PIN rf_wr_reg_o[1]
    PORT
      LAYER met3 ;
        RECT 0.000 17.720 4.000 18.320 ;
    END
  END rf_wr_reg_o[1]
  PIN rf_wr_reg_o[2]
    PORT
      LAYER met3 ;
        RECT 0.000 19.080 4.000 19.680 ;
    END
  END rf_wr_reg_o[2]
  PIN rf_wr_reg_o[3]
    PORT
      LAYER met3 ;
        RECT 0.000 20.440 4.000 21.040 ;
    END
  END rf_wr_reg_o[3]
  PIN rf_wr_reg_o[4]
    PORT
      LAYER met3 ;
        RECT 0.000 21.800 4.000 22.400 ;
    END
  END rf_wr_reg_o[4]
  PIN rst_ni
    PORT
      LAYER met2 ;
        RECT 62.190 296.000 62.470 300.000 ;
    END
  END rst_ni
  OBS
      LAYER li1 ;
        RECT 5.520 10.795 244.260 288.405 ;
      LAYER met1 ;
        RECT 4.670 5.820 248.790 288.960 ;
      LAYER met2 ;
        RECT 4.300 295.720 61.910 296.000 ;
        RECT 62.750 295.720 186.570 296.000 ;
        RECT 187.410 295.720 248.760 296.000 ;
        RECT 4.300 2.875 248.760 295.720 ;
      LAYER met3 ;
        RECT 4.400 290.720 246.000 294.265 ;
        RECT 4.400 289.320 245.600 290.720 ;
        RECT 4.400 288.000 246.000 289.320 ;
        RECT 4.400 286.600 245.600 288.000 ;
        RECT 4.400 285.280 246.000 286.600 ;
        RECT 4.400 283.880 245.600 285.280 ;
        RECT 4.400 282.560 246.000 283.880 ;
        RECT 4.400 281.160 245.600 282.560 ;
        RECT 4.400 279.840 246.000 281.160 ;
        RECT 4.400 278.440 245.600 279.840 ;
        RECT 4.400 277.120 246.000 278.440 ;
        RECT 4.400 275.720 245.600 277.120 ;
        RECT 4.400 274.400 246.000 275.720 ;
        RECT 4.400 273.000 245.600 274.400 ;
        RECT 4.400 271.680 246.000 273.000 ;
        RECT 4.400 270.280 245.600 271.680 ;
        RECT 4.400 268.960 246.000 270.280 ;
        RECT 4.400 267.560 245.600 268.960 ;
        RECT 4.400 266.240 246.000 267.560 ;
        RECT 4.400 264.840 245.600 266.240 ;
        RECT 4.400 263.520 246.000 264.840 ;
        RECT 4.400 262.120 245.600 263.520 ;
        RECT 4.400 260.800 246.000 262.120 ;
        RECT 4.400 259.400 245.600 260.800 ;
        RECT 4.400 258.080 246.000 259.400 ;
        RECT 4.400 256.680 245.600 258.080 ;
        RECT 4.400 255.360 246.000 256.680 ;
        RECT 4.400 253.960 245.600 255.360 ;
        RECT 4.400 252.640 246.000 253.960 ;
        RECT 4.400 251.240 245.600 252.640 ;
        RECT 4.400 249.920 246.000 251.240 ;
        RECT 4.400 248.520 245.600 249.920 ;
        RECT 4.400 247.200 246.000 248.520 ;
        RECT 4.400 245.800 245.600 247.200 ;
        RECT 4.400 244.480 246.000 245.800 ;
        RECT 4.400 243.080 245.600 244.480 ;
        RECT 4.400 241.760 246.000 243.080 ;
        RECT 4.400 240.360 245.600 241.760 ;
        RECT 4.400 239.040 246.000 240.360 ;
        RECT 4.400 237.640 245.600 239.040 ;
        RECT 4.400 236.320 246.000 237.640 ;
        RECT 4.400 234.920 245.600 236.320 ;
        RECT 4.400 233.600 246.000 234.920 ;
        RECT 4.400 232.200 245.600 233.600 ;
        RECT 4.400 230.880 246.000 232.200 ;
        RECT 4.400 229.480 245.600 230.880 ;
        RECT 4.400 228.160 246.000 229.480 ;
        RECT 4.400 226.760 245.600 228.160 ;
        RECT 4.400 225.440 246.000 226.760 ;
        RECT 4.400 224.040 245.600 225.440 ;
        RECT 4.400 222.720 246.000 224.040 ;
        RECT 4.400 221.320 245.600 222.720 ;
        RECT 4.400 220.000 246.000 221.320 ;
        RECT 4.400 218.600 245.600 220.000 ;
        RECT 4.400 217.280 246.000 218.600 ;
        RECT 4.400 215.880 245.600 217.280 ;
        RECT 4.400 214.560 246.000 215.880 ;
        RECT 4.400 213.160 245.600 214.560 ;
        RECT 4.400 211.840 246.000 213.160 ;
        RECT 4.400 210.440 245.600 211.840 ;
        RECT 4.400 209.120 246.000 210.440 ;
        RECT 4.400 207.720 245.600 209.120 ;
        RECT 4.400 206.400 246.000 207.720 ;
        RECT 4.400 205.000 245.600 206.400 ;
        RECT 4.400 203.680 246.000 205.000 ;
        RECT 4.400 202.280 245.600 203.680 ;
        RECT 4.400 200.960 246.000 202.280 ;
        RECT 4.400 199.560 245.600 200.960 ;
        RECT 4.400 198.240 246.000 199.560 ;
        RECT 4.400 196.840 245.600 198.240 ;
        RECT 4.400 195.520 246.000 196.840 ;
        RECT 4.400 194.120 245.600 195.520 ;
        RECT 4.400 192.800 246.000 194.120 ;
        RECT 4.400 191.400 245.600 192.800 ;
        RECT 4.400 190.080 246.000 191.400 ;
        RECT 4.400 188.680 245.600 190.080 ;
        RECT 4.400 187.360 246.000 188.680 ;
        RECT 4.400 185.960 245.600 187.360 ;
        RECT 4.400 184.640 246.000 185.960 ;
        RECT 4.400 183.240 245.600 184.640 ;
        RECT 4.400 181.920 246.000 183.240 ;
        RECT 4.400 180.520 245.600 181.920 ;
        RECT 4.400 179.200 246.000 180.520 ;
        RECT 4.400 177.800 245.600 179.200 ;
        RECT 4.400 176.480 246.000 177.800 ;
        RECT 4.400 175.080 245.600 176.480 ;
        RECT 4.400 173.760 246.000 175.080 ;
        RECT 4.400 172.360 245.600 173.760 ;
        RECT 4.400 171.040 246.000 172.360 ;
        RECT 4.400 169.640 245.600 171.040 ;
        RECT 4.400 168.320 246.000 169.640 ;
        RECT 4.400 166.920 245.600 168.320 ;
        RECT 4.400 165.600 246.000 166.920 ;
        RECT 4.400 164.200 245.600 165.600 ;
        RECT 4.400 162.880 246.000 164.200 ;
        RECT 4.400 161.480 245.600 162.880 ;
        RECT 4.400 160.160 246.000 161.480 ;
        RECT 4.400 158.760 245.600 160.160 ;
        RECT 4.400 157.440 246.000 158.760 ;
        RECT 4.400 156.040 245.600 157.440 ;
        RECT 4.400 154.720 246.000 156.040 ;
        RECT 4.400 153.320 245.600 154.720 ;
        RECT 4.400 152.000 246.000 153.320 ;
        RECT 4.400 150.600 245.600 152.000 ;
        RECT 4.400 149.280 246.000 150.600 ;
        RECT 4.400 147.880 245.600 149.280 ;
        RECT 4.400 146.560 246.000 147.880 ;
        RECT 4.400 145.160 245.600 146.560 ;
        RECT 4.400 143.840 246.000 145.160 ;
        RECT 4.400 142.440 245.600 143.840 ;
        RECT 4.400 141.120 246.000 142.440 ;
        RECT 4.400 139.720 245.600 141.120 ;
        RECT 4.400 138.400 246.000 139.720 ;
        RECT 4.400 137.000 245.600 138.400 ;
        RECT 4.400 135.680 246.000 137.000 ;
        RECT 4.400 134.280 245.600 135.680 ;
        RECT 4.400 132.960 246.000 134.280 ;
        RECT 4.400 131.560 245.600 132.960 ;
        RECT 4.400 130.240 246.000 131.560 ;
        RECT 4.400 128.840 245.600 130.240 ;
        RECT 4.400 127.520 246.000 128.840 ;
        RECT 4.400 126.120 245.600 127.520 ;
        RECT 4.400 124.800 246.000 126.120 ;
        RECT 4.400 123.400 245.600 124.800 ;
        RECT 4.400 122.080 246.000 123.400 ;
        RECT 4.400 120.680 245.600 122.080 ;
        RECT 4.400 119.360 246.000 120.680 ;
        RECT 4.400 117.960 245.600 119.360 ;
        RECT 4.400 116.640 246.000 117.960 ;
        RECT 4.400 115.240 245.600 116.640 ;
        RECT 4.400 113.920 246.000 115.240 ;
        RECT 4.400 112.520 245.600 113.920 ;
        RECT 4.400 111.200 246.000 112.520 ;
        RECT 4.400 109.800 245.600 111.200 ;
        RECT 4.400 108.480 246.000 109.800 ;
        RECT 4.400 107.080 245.600 108.480 ;
        RECT 4.400 105.760 246.000 107.080 ;
        RECT 4.400 104.360 245.600 105.760 ;
        RECT 4.400 103.040 246.000 104.360 ;
        RECT 4.400 101.640 245.600 103.040 ;
        RECT 4.400 100.320 246.000 101.640 ;
        RECT 4.400 98.920 245.600 100.320 ;
        RECT 4.400 97.600 246.000 98.920 ;
        RECT 4.400 96.200 245.600 97.600 ;
        RECT 4.400 94.880 246.000 96.200 ;
        RECT 4.400 93.480 245.600 94.880 ;
        RECT 4.400 92.160 246.000 93.480 ;
        RECT 4.400 90.760 245.600 92.160 ;
        RECT 4.400 89.440 246.000 90.760 ;
        RECT 4.400 88.040 245.600 89.440 ;
        RECT 4.400 86.720 246.000 88.040 ;
        RECT 4.400 85.320 245.600 86.720 ;
        RECT 4.400 84.000 246.000 85.320 ;
        RECT 4.400 82.600 245.600 84.000 ;
        RECT 4.400 81.280 246.000 82.600 ;
        RECT 4.400 79.880 245.600 81.280 ;
        RECT 4.400 78.560 246.000 79.880 ;
        RECT 4.400 77.160 245.600 78.560 ;
        RECT 4.400 75.840 246.000 77.160 ;
        RECT 4.400 74.440 245.600 75.840 ;
        RECT 4.400 73.120 246.000 74.440 ;
        RECT 4.400 71.720 245.600 73.120 ;
        RECT 4.400 70.400 246.000 71.720 ;
        RECT 4.400 69.000 245.600 70.400 ;
        RECT 4.400 67.680 246.000 69.000 ;
        RECT 4.400 66.280 245.600 67.680 ;
        RECT 4.400 64.960 246.000 66.280 ;
        RECT 4.400 63.560 245.600 64.960 ;
        RECT 4.400 62.240 246.000 63.560 ;
        RECT 4.400 60.840 245.600 62.240 ;
        RECT 4.400 59.520 246.000 60.840 ;
        RECT 4.400 58.120 245.600 59.520 ;
        RECT 4.400 56.800 246.000 58.120 ;
        RECT 4.400 55.400 245.600 56.800 ;
        RECT 4.400 54.080 246.000 55.400 ;
        RECT 4.400 52.680 245.600 54.080 ;
        RECT 4.400 51.360 246.000 52.680 ;
        RECT 4.400 49.960 245.600 51.360 ;
        RECT 4.400 48.640 246.000 49.960 ;
        RECT 4.400 47.240 245.600 48.640 ;
        RECT 4.400 45.920 246.000 47.240 ;
        RECT 4.400 44.520 245.600 45.920 ;
        RECT 4.400 43.200 246.000 44.520 ;
        RECT 4.400 41.800 245.600 43.200 ;
        RECT 4.400 40.480 246.000 41.800 ;
        RECT 4.400 39.080 245.600 40.480 ;
        RECT 4.400 37.760 246.000 39.080 ;
        RECT 4.400 36.360 245.600 37.760 ;
        RECT 4.400 35.040 246.000 36.360 ;
        RECT 4.400 33.640 245.600 35.040 ;
        RECT 4.400 32.320 246.000 33.640 ;
        RECT 4.400 30.920 245.600 32.320 ;
        RECT 4.400 29.600 246.000 30.920 ;
        RECT 4.400 28.200 245.600 29.600 ;
        RECT 4.400 26.880 246.000 28.200 ;
        RECT 4.400 25.480 245.600 26.880 ;
        RECT 4.400 24.160 246.000 25.480 ;
        RECT 4.400 22.760 245.600 24.160 ;
        RECT 4.400 21.440 246.000 22.760 ;
        RECT 4.400 20.040 245.600 21.440 ;
        RECT 4.400 18.720 246.000 20.040 ;
        RECT 4.400 17.320 245.600 18.720 ;
        RECT 4.400 16.000 246.000 17.320 ;
        RECT 4.400 14.600 245.600 16.000 ;
        RECT 4.400 13.280 246.000 14.600 ;
        RECT 4.400 11.880 245.600 13.280 ;
        RECT 4.400 10.560 246.000 11.880 ;
        RECT 4.400 9.160 245.600 10.560 ;
        RECT 4.400 2.895 246.000 9.160 ;
      LAYER met4 ;
        RECT 7.655 19.895 20.640 284.065 ;
        RECT 23.040 19.895 23.940 284.065 ;
        RECT 26.340 19.895 174.240 284.065 ;
        RECT 176.640 19.895 177.540 284.065 ;
        RECT 179.940 19.895 206.705 284.065 ;
      LAYER met5 ;
        RECT 47.500 186.410 181.580 189.500 ;
        RECT 47.500 174.300 181.580 178.310 ;
  END
END core
END LIBRARY

